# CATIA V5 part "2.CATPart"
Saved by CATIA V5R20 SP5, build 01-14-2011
Part number: Part1
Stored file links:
  E:\scc\zuoye.CATPart

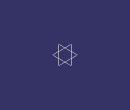
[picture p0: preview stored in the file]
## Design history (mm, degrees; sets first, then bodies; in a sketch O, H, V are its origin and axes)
Body1 (main body)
